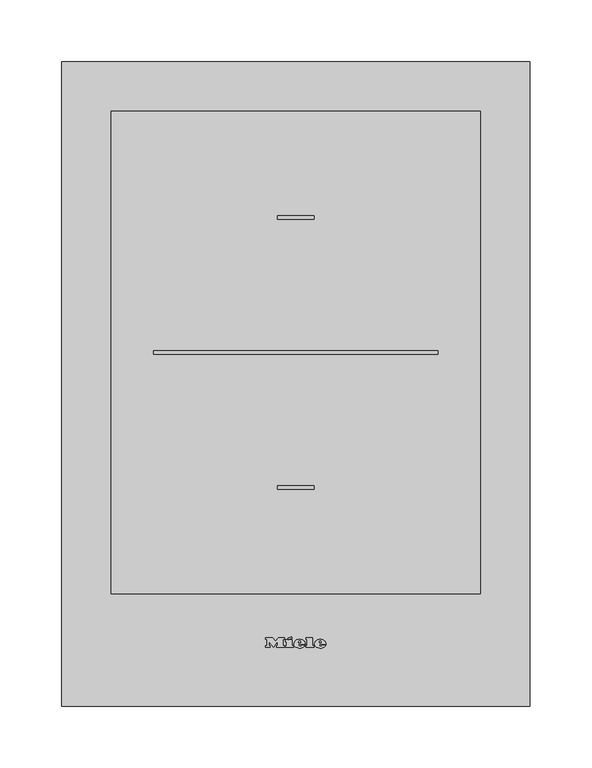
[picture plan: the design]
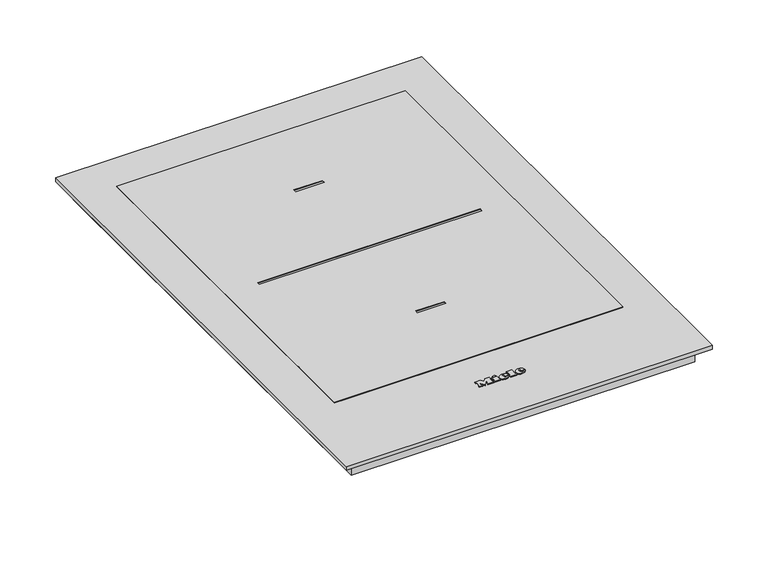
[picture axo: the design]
"""IFC4 building model written with IfcOpenShell, lengths in millimetres: proxy geometry."""

from ifc_helpers import new_model, si_unit, point, frame, frame_2d, origin, origin_with_axes, place, context, project, spatial, polyline, circle_curve, ellipse_curve, trimmed, segment, composite_curve, outline, extrude, source, transform, mapped, element, save
from ifc_brep_helpers import plane_surface, cylinder_surface, revolved_surface, extruded_surface, advanced_brep


def specialty_equipment_049aa171(model_context):
    return source(origin(), model_context, "Body", "SolidModel", [
        advanced_brep(
        [(19.06, 49.1959995, 4.9919765), (19.06, 50.0039992, 4.9925904), (24.412, 50.0039992, 4.9925904), (15.1, 50.0039992, 4.9925904), (17.3, 47.3, 4.990536), (24.276, 49.1959995, 4.9919765), (21.86, 49.1959995, 4.9919765), (19.956, 48.2999997, 4.9912958), (19.06, 51.0279989, 4.9933684), (19.06, 51.8999987, 4.9940309), (20.428, 51.8999987, 4.9940309), (20.428, 51.0279989, 4.9933684), (19.06, 49.1967592, 3.9919768), (19.956, 48.3007595, 3.9912961), (21.86, 49.1967592, 3.9919768), (24.276, 49.1967592, 3.9919768), (17.3, 47.3007598, 3.9905363), (15.1, 50.004759, 3.9925907), (24.412, 50.004759, 3.9925907), (19.06, 50.004759, 3.9925907), (19.06, 51.0287587, 3.9933687), (20.428, 51.0287587, 3.9933687), (20.428, 51.9007584, 3.9940312), (19.06, 51.9007584, 3.9940312)],
        [
            (0, 1),
            (1, 2),
            (2, 3, ellipse_curve(frame((19.756, 50.0039992, 4.9925904), z_axis=(0.0, -0.0007597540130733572, 0.9999997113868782), x_axis=(-1.0, 0.0, 0.0)), 4.656, 3.848)),
            (3, 4, circle_curve(frame((18.1960436, 50.2759991, 4.9927971), z_axis=(0.0, -0.0007597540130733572, 0.9999997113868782), x_axis=(0.0, -0.9999997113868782, -0.0007597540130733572)), 3.1079688)),
            (4, 5, circle_curve(frame((19.6627936, 52.3879985, 4.9944017), z_axis=(0.0, -0.0007597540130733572, 0.9999997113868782), x_axis=(0.0, -0.9999997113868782, -0.0007597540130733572)), 5.6098607)),
            (5, 6),
            (6, 7, circle_curve(frame((20.3470588, 49.9399992, 4.9925418), z_axis=(0.0, 0.0007597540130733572, -0.9999997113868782), x_axis=(0.0, -0.9999997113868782, -0.0007597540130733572)), 1.6859795)),
            (7, 0, circle_curve(frame((19.956, 49.1959995, 4.9919765), z_axis=(0.0, 0.0007597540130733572, -0.9999997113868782), x_axis=(0.0, -0.9999997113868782, -0.0007597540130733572)), 0.896)),
            (8, 9),
            (9, 10, circle_curve(frame((19.744, 51.8999987, 4.9940309), z_axis=(0.0, 0.0007597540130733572, -0.9999997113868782), x_axis=(0.0, -0.9999997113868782, -0.0007597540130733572)), 0.684)),
            (10, 11),
            (11, 8),
            (12, 13, circle_curve(frame((19.956, 49.1967592, 3.9919768), z_axis=(0.0, -0.0007597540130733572, 0.9999997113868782), x_axis=(0.0, -0.9999997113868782, -0.0007597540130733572)), 0.896)),
            (13, 14, circle_curve(frame((20.3470588, 49.940759, 3.9925421), z_axis=(0.0, -0.0007597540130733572, 0.9999997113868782), x_axis=(0.0, -0.9999997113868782, -0.0007597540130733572)), 1.6859795)),
            (14, 15),
            (15, 16, circle_curve(frame((19.6627936, 52.3887583, 3.994402), z_axis=(0.0, 0.0007597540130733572, -0.9999997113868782), x_axis=(0.0, -0.9999997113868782, -0.0007597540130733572)), 5.6098607)),
            (16, 17, circle_curve(frame((18.1960436, 50.2767589, 3.9927974), z_axis=(0.0, 0.0007597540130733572, -0.9999997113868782), x_axis=(0.0, -0.9999997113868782, -0.0007597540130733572)), 3.1079688)),
            (17, 18, ellipse_curve(frame((19.756, 50.004759, 3.9925907), z_axis=(0.0, 0.0007597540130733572, -0.9999997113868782), x_axis=(-1.0, 0.0, 0.0)), 4.656, 3.848)),
            (18, 19),
            (19, 12),
            (20, 21),
            (21, 22),
            (22, 23, circle_curve(frame((19.744, 51.9007584, 3.9940312), z_axis=(0.0, -0.0007597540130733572, 0.9999997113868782), x_axis=(0.0, -0.9999997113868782, -0.0007597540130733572)), 0.684)),
            (23, 20),
            (0, 12),
            (19, 1),
            (18, 2),
            (5, 15),
            (14, 6),
            (17, 3),
            (13, 7),
            (16, 4),
            (8, 20),
            (23, 9),
            (22, 10),
            (21, 11),
        ],
        [
            plane_surface(frame((19.06, 50.0039992, 4.9925904), z_axis=(0.0, -0.0007597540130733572, 0.9999997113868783), x_axis=(0.0, 0.9999997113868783, 0.0007597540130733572))),
            plane_surface(frame((19.06, 50.004759, 3.9925907), z_axis=(0.0, 0.0007597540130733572, -0.9999997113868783), x_axis=(0.0, -0.9999997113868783, -0.0007597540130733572))),
            plane_surface(frame((19.06, 49.1959995, 4.9919765), z_axis=(1.0, 0.0, 0.0), x_axis=(0.0, 0.0007597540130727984, -0.9999997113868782))),
            plane_surface(frame((19.06, 50.0039992, 4.9925904), z_axis=(0.0, -0.9999997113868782, -0.0007597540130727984), x_axis=(0.0, 0.0007597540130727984, -0.9999997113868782))),
            plane_surface(frame((24.276, 49.1959995, 4.9919765), z_axis=(0.0, 0.9999997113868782, 0.0007597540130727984), x_axis=(0.0, 0.0007597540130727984, -0.9999997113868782))),
            extruded_surface(trimmed(ellipse_curve(frame((19.756, 50.0055187, 2.992591), z_axis=(0.0, -0.0007597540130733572, 0.9999997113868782), x_axis=(-1.0, 0.0, 0.0)), 4.656, 3.848), [point((24.412, 50.0055187, 2.992591))], [point((15.1, 50.0055187, 2.992591))], True, "CARTESIAN"), (0.0, -0.0007597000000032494, 0.9999997), 0.9999999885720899),
            revolved_surface(polyline([(20.3470588, 48.25477998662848, 3.9912611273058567), (20.3470588, 48.25402023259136, 4.991260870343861)]), (20.3470588, 49.940759, 3.9925421), (0.0, 0.0007597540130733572, -0.9999997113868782)),
            revolved_surface(polyline([(19.956, 48.30075945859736, 3.9912960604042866), (19.956, 48.29999970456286, 4.991295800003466)]), (19.956, 49.1967592, 3.9919768), (0.0, 0.0007597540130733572, -0.9999997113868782)),
            cylinder_surface(frame((18.1960436, 50.2767589, 3.9927974), z_axis=(0.0, -0.0007597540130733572, 0.9999997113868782), x_axis=(0.0, -0.9999997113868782, -0.0007597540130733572)), 3.1079688),
            cylinder_surface(frame((19.6627936, 52.3887583, 3.994402), z_axis=(0.0, -0.0007597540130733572, 0.9999997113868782), x_axis=(0.0, -0.9999997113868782, -0.0007597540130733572)), 5.6098607),
            plane_surface(frame((19.06, 51.0279989, 4.9933684), z_axis=(1.0, 0.0, 0.0), x_axis=(0.0, 0.0007597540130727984, -0.9999997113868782))),
            revolved_surface(polyline([(19.744, 51.21675859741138, 3.9935115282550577), (19.744, 51.215998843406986, 4.993511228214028)]), (19.744, 51.9007584, 3.9940312), (0.0, 0.0007597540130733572, -0.9999997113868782)),
            plane_surface(frame((20.428, 51.8999987, 4.9940309), z_axis=(-1.0, 0.0, 0.0), x_axis=(0.0, 0.0007597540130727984, -0.9999997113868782))),
            plane_surface(frame((20.428, 51.0279989, 4.9933684), z_axis=(0.0, 0.9999997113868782, 0.0007597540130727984), x_axis=(0.0, 0.0007597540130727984, -0.9999997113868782))),
        ],
        [
            (0, [[1, 2, 3, 4, 5, 6, 7, 8], [9, 10, 11, 12]]),
            (1, [[13, 14, 15, 16, 17, 18, 19, 20], [21, 22, 23, 24]]),
            (2, [[-1, 25, -20, 26]]),
            (3, [[-2, -26, -19, 27]]),
            (4, [[-6, 28, -15, 29]]),
            (5, [[-3, -27, -18, 30]]),
            (6, [[-7, -29, -14, 31]]),
            (7, [[-8, -31, -13, -25]]),
            (8, [[-4, -30, -17, 32]]),
            (9, [[-5, -32, -16, -28]]),
            (10, [[-9, 33, -24, 34]]),
            (11, [[-10, -34, -23, 35]]),
            (12, [[-11, -35, -22, 36]]),
            (13, [[-12, -36, -21, -33]]),
        ],
    ),
        advanced_brep(
        [(2.364, 49.1959995, 4.9919765), (2.364, 50.0039992, 4.9925904), (7.716, 50.0039992, 4.9925904), (-1.596, 50.0039992, 4.9925904), (0.604, 47.3, 4.990536), (7.58, 49.1959995, 4.9919765), (5.164, 49.1959995, 4.9919765), (3.26, 48.2999997, 4.9912958), (2.364, 51.0279989, 4.9933684), (2.364, 51.8999987, 4.9940309), (3.732, 51.8999987, 4.9940309), (3.732, 51.0279989, 4.9933684), (2.364, 49.1967592, 3.9919768), (3.26, 48.3007595, 3.9912961), (5.164, 49.1967592, 3.9919768), (7.58, 49.1967592, 3.9919768), (0.604, 47.3007598, 3.9905363), (-1.596, 50.004759, 3.9925907), (7.716, 50.004759, 3.9925907), (2.364, 50.004759, 3.9925907), (2.364, 51.0287587, 3.9933687), (3.732, 51.0287587, 3.9933687), (3.732, 51.9007584, 3.9940312), (2.364, 51.9007584, 3.9940312)],
        [
            (0, 1),
            (1, 2),
            (2, 3, ellipse_curve(frame((3.06, 50.0039992, 4.9925904), z_axis=(0.0, -0.0007597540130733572, 0.9999997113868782), x_axis=(-1.0, 0.0, 0.0)), 4.656, 3.848)),
            (3, 4, circle_curve(frame((1.5000436, 50.2759991, 4.9927971), z_axis=(0.0, -0.0007597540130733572, 0.9999997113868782), x_axis=(0.0, -0.9999997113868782, -0.0007597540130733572)), 3.1079688)),
            (4, 5, circle_curve(frame((2.9667936, 52.3879985, 4.9944017), z_axis=(0.0, -0.0007597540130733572, 0.9999997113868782), x_axis=(0.0, -0.9999997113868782, -0.0007597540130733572)), 5.6098607)),
            (5, 6),
            (6, 7, circle_curve(frame((3.6510588, 49.9399992, 4.9925418), z_axis=(0.0, 0.0007597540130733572, -0.9999997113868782), x_axis=(0.0, -0.9999997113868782, -0.0007597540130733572)), 1.6859795)),
            (7, 0, circle_curve(frame((3.26, 49.1959995, 4.9919765), z_axis=(0.0, 0.0007597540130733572, -0.9999997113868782), x_axis=(0.0, -0.9999997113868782, -0.0007597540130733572)), 0.896)),
            (8, 9),
            (9, 10, circle_curve(frame((3.048, 51.8999987, 4.9940309), z_axis=(0.0, 0.0007597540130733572, -0.9999997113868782), x_axis=(0.0, -0.9999997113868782, -0.0007597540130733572)), 0.684)),
            (10, 11),
            (11, 8),
            (12, 13, circle_curve(frame((3.26, 49.1967592, 3.9919768), z_axis=(0.0, -0.0007597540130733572, 0.9999997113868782), x_axis=(0.0, -0.9999997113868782, -0.0007597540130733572)), 0.896)),
            (13, 14, circle_curve(frame((3.6510588, 49.940759, 3.9925421), z_axis=(0.0, -0.0007597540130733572, 0.9999997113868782), x_axis=(0.0, -0.9999997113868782, -0.0007597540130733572)), 1.6859795)),
            (14, 15),
            (15, 16, circle_curve(frame((2.9667936, 52.3887583, 3.994402), z_axis=(0.0, 0.0007597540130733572, -0.9999997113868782), x_axis=(0.0, -0.9999997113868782, -0.0007597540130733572)), 5.6098607)),
            (16, 17, circle_curve(frame((1.5000436, 50.2767589, 3.9927974), z_axis=(0.0, 0.0007597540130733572, -0.9999997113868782), x_axis=(0.0, -0.9999997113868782, -0.0007597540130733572)), 3.1079688)),
            (17, 18, ellipse_curve(frame((3.06, 50.004759, 3.9925907), z_axis=(0.0, 0.0007597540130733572, -0.9999997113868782), x_axis=(-1.0, 0.0, 0.0)), 4.656, 3.848)),
            (18, 19),
            (19, 12),
            (20, 21),
            (21, 22),
            (22, 23, circle_curve(frame((3.048, 51.9007584, 3.9940312), z_axis=(0.0, -0.0007597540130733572, 0.9999997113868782), x_axis=(0.0, -0.9999997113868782, -0.0007597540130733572)), 0.684)),
            (23, 20),
            (0, 12),
            (19, 1),
            (18, 2),
            (5, 15),
            (14, 6),
            (17, 3),
            (13, 7),
            (16, 4),
            (8, 20),
            (23, 9),
            (22, 10),
            (21, 11),
        ],
        [
            plane_surface(frame((2.364, 50.0039992, 4.9925904), z_axis=(0.0, -0.0007597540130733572, 0.9999997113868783), x_axis=(0.0, 0.9999997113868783, 0.0007597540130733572))),
            plane_surface(frame((2.364, 50.004759, 3.9925907), z_axis=(0.0, 0.0007597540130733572, -0.9999997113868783), x_axis=(0.0, -0.9999997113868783, -0.0007597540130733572))),
            plane_surface(frame((2.364, 49.1959995, 4.9919765), z_axis=(1.0, 0.0, 0.0), x_axis=(0.0, 0.0007597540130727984, -0.9999997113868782))),
            plane_surface(frame((2.364, 50.0039992, 4.9925904), z_axis=(0.0, -0.9999997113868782, -0.0007597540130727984), x_axis=(0.0, 0.0007597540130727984, -0.9999997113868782))),
            plane_surface(frame((7.58, 49.1959995, 4.9919765), z_axis=(0.0, 0.9999997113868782, 0.0007597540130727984), x_axis=(0.0, 0.0007597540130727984, -0.9999997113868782))),
            extruded_surface(trimmed(ellipse_curve(frame((3.06, 50.0055187, 2.992591), z_axis=(0.0, -0.0007597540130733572, 0.9999997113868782), x_axis=(-1.0, 0.0, 0.0)), 4.656, 3.848), [point((7.716, 50.0055187, 2.992591))], [point((-1.596, 50.0055187, 2.992591))], True, "CARTESIAN"), (0.0, -0.0007597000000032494, 0.9999997), 0.9999999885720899),
            revolved_surface(polyline([(3.6510588, 48.25477998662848, 3.9912611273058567), (3.6510588, 48.25402023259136, 4.991260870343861)]), (3.6510588, 49.940759, 3.9925421), (0.0, 0.0007597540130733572, -0.9999997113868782)),
            revolved_surface(polyline([(3.26, 48.30075945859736, 3.9912960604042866), (3.26, 48.29999970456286, 4.991295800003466)]), (3.26, 49.1967592, 3.9919768), (0.0, 0.0007597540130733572, -0.9999997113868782)),
            cylinder_surface(frame((1.5000436, 50.2767589, 3.9927974), z_axis=(0.0, -0.0007597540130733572, 0.9999997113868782), x_axis=(0.0, -0.9999997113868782, -0.0007597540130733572)), 3.1079688),
            cylinder_surface(frame((2.9667936, 52.3887583, 3.994402), z_axis=(0.0, -0.0007597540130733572, 0.9999997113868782), x_axis=(0.0, -0.9999997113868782, -0.0007597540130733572)), 5.6098607),
            plane_surface(frame((2.364, 51.0279989, 4.9933684), z_axis=(1.0, 0.0, 0.0), x_axis=(0.0, 0.0007597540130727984, -0.9999997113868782))),
            revolved_surface(polyline([(3.048, 51.21675859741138, 3.9935115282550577), (3.048, 51.215998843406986, 4.993511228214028)]), (3.048, 51.9007584, 3.9940312), (0.0, 0.0007597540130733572, -0.9999997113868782)),
            plane_surface(frame((3.732, 51.8999987, 4.9940309), z_axis=(-1.0, 0.0, 0.0), x_axis=(0.0, 0.0007597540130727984, -0.9999997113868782))),
            plane_surface(frame((3.732, 51.0279989, 4.9933684), z_axis=(0.0, 0.9999997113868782, 0.0007597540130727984), x_axis=(0.0, 0.0007597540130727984, -0.9999997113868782))),
        ],
        [
            (0, [[1, 2, 3, 4, 5, 6, 7, 8], [9, 10, 11, 12]]),
            (1, [[13, 14, 15, 16, 17, 18, 19, 20], [21, 22, 23, 24]]),
            (2, [[-1, 25, -20, 26]]),
            (3, [[-2, -26, -19, 27]]),
            (4, [[-6, 28, -15, 29]]),
            (5, [[-3, -27, -18, 30]]),
            (6, [[-7, -29, -14, 31]]),
            (7, [[-8, -31, -13, -25]]),
            (8, [[-4, -30, -17, 32]]),
            (9, [[-5, -32, -16, -28]]),
            (10, [[-9, 33, -24, 34]]),
            (11, [[-10, -34, -23, 35]]),
            (12, [[-11, -35, -22, 36]]),
            (13, [[-12, -36, -21, -33]]),
        ],
    ),
        extrude(outline(polyline([(0.0, 0.0), (-0.0109086, -2.9993294), (-1.4390415, -2.9920868), (-1.4315306, 0.0), (0.0, 0.0)])), frame((-6.38, 54.8287576, 3.9962558), z_axis=(0.0, -0.0007597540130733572, 0.9999997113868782), x_axis=(-0.42472021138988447, 0.9053243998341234, 0.0006878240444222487)), (0.0, 0.0, 1.0), 1.0),
        extrude(outline(polyline([(-0.4933908, 2.4141097), (-2.7800844, -2.4601583), (-7.0459742, -0.4588767), (-7.4401145, -1.2990179), (-8.6568709, -0.728194), (-5.9760369, 4.9862153), (-4.7592806, 4.4153913), (-5.1636142, 3.5535222), (-2.1941494, 2.16044), (-1.7898157, 3.022309), (-0.4933908, 2.4141097)])), frame((-6.38, 54.8287576, 3.9962558), z_axis=(0.0, -0.0007597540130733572, 0.9999997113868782), x_axis=(-0.42472021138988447, 0.9053243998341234, 0.0006878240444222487)), (0.0, 0.0, 1.0), 1.0),
        extrude(outline(polyline([(0.0, 0.0), (0.0, -1.304), (-5.504, -1.304), (-5.504, 5.3519999), (-6.488, 5.3519999), (-6.488, 6.6959999), (0.0, 6.6959999), (0.0, 5.3519999), (-0.96, 5.3519999), (-0.96, 0.0), (0.0, 0.0)])), frame((8.164, 53.9967578, 3.9956236), z_axis=(0.0, -0.0007597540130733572, 0.9999997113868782), x_axis=(-1.0, 0.0, 0.0)), (0.0, 0.0, 1.0), 1.0),
        extrude(outline(polyline([(0.0, 0.0), (0.0, -1.304), (-5.576, -1.304), (-7.92, 1.696), (-10.256, -1.304), (-15.128, -1.304), (-15.128, 0.0), (-14.112, 0.0), (-14.112, 5.3519999), (-15.128, 5.3519999), (-15.128, 6.6959999), (-8.744, 6.6959999), (-8.744, 5.3519999), (-9.728, 5.3519999), (-9.728, 1.8807776), (-6.136, 6.6959999), (-2.56, 1.9488753), (-2.56, 5.3519999), (-3.52, 5.3519999), (-3.52, 6.6959999), (0.0, 6.6959999), (0.0, 5.3519999), (-0.968, 5.3519999), (-0.968, 0.0), (0.0, 0.0)])), frame((-24.3, 53.9967578, 3.9956236), z_axis=(0.0, -0.0007597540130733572, 0.9999997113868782), x_axis=(-1.0, 0.0, 0.0)), (0.0, 0.0, 1.0), 1.0),
        extrude(outline(polyline([(189.0, 520.0), (189.0, 0.0), (-189.0, 0.0), (-189.0, 520.0), (189.0, 520.0)])), origin_with_axes(), (0.0, 0.0, 1.0), 4.0),
        extrude(outline(polyline([(-119.0, 91.3), (-119.0, 468.3), (119.0, 468.3), (119.0, 433.7), (153.5, 433.7), (153.5, 183.5), (119.0, 183.5), (119.0, 91.3), (-119.0, 91.3)])), frame((0.0, 0.0, -46.5), z_axis=(0.0, 0.0, 1.0), x_axis=(1.0, 0.0, 0.0)), (0.0, 0.0, 1.0), 29.7),
        extrude(outline(polyline([(177.5, 508.5), (177.5, 11.5), (-177.5, 11.5), (-177.5, 508.5), (177.5, 508.5)])), frame((0.0, 0.0, -16.8), z_axis=(0.0, 0.0, 1.0), x_axis=(1.0, 0.0, 0.0)), (0.0, 0.0, 1.0), 16.8),
        extrude(outline(polyline([(447.3772603, -29.0), (440.0, -29.0), (440.0, -27.7442961), (446.1215564, -27.7442961), (446.1215564, -24.4480734), (440.470889, -24.4480734), (440.470889, -23.1923696), (446.1215564, -23.1923696), (446.1215564, -20.2100729), (440.156963, -20.2100729), (440.156963, -18.954369), (447.3772603, -18.954369), (447.3772603, -29.0)])), frame((-150.0, 0.0, 0.0), z_axis=(1.0, 0.0, 0.0), x_axis=(0.0, 1.0, 0.0)), (0.0, 0.0, 1.0), 1.0),
        extrude(outline(polyline([(438.1164442, -29.0), (431.8379248, -29.0), (431.8379248, -27.7442961), (436.8607403, -27.7442961), (436.8607403, -18.954369), (438.1164442, -18.954369), (438.1164442, -29.0)])), frame((-150.0, 0.0, 0.0), z_axis=(1.0, 0.0, 0.0), x_axis=(0.0, 1.0, 0.0)), (0.0, 0.0, 1.0), 1.0),
        extrude(outline(composite_curve([segment(trimmed(circle_curve(frame_2d((440.0, -24.0)), 8.0), [point((448.0, -24.0))], [point((432.0, -24.0))], False, "CARTESIAN"), True, "CONTINUOUS"), segment(trimmed(circle_curve(frame_2d((440.0, -24.0)), 8.0), [point((432.0, -24.0))], [point((448.0, -24.0))], False, "CARTESIAN"), True, "CONTINUOUS")], self_intersect=False)), frame((-149.0, 0.0, 0.0), z_axis=(1.0, 0.0, 0.0), x_axis=(0.0, 1.0, 0.0)), (0.0, 0.0, 1.0), 30.0),
        extrude(outline(polyline([(149.0, 480.0), (149.0, 90.8), (-149.0, 90.8), (-149.0, 480.0), (149.0, 480.0)]), holes=[polyline([(14.7, 395.95), (-14.7, 395.95), (-14.7, 392.85), (14.7, 392.85), (14.7, 395.95)]), polyline([(115.0, 286.95), (-115.0, 286.95), (-115.0, 283.85), (115.0, 283.85), (115.0, 286.95)]), polyline([(14.7, 177.95), (-14.7, 177.95), (-14.7, 174.85), (14.7, 174.85), (14.7, 177.95)])]), frame((0.0, 0.0, 4.0), z_axis=(0.0, 0.0, 1.0), x_axis=(1.0, 0.0, 0.0)), (0.0, 0.0, 1.0), 1.0),
    ])


if __name__ == "__main__":
    model = new_model("IFC4")
    model_context = context("Model", 3, world=origin())
    ifc_project = project(units=[si_unit("LENGTHUNIT", "METRE", prefix="MILLI")], contexts=[model_context])
    site = spatial("IfcSite", under=ifc_project)
    building = spatial("IfcBuilding", under=site)
    placement = place(None, origin())
    specialty_equipment_shape = specialty_equipment_049aa171(model_context)
    element("IfcBuildingElementProxy", 1, Name="Specialty Equipment", at=placement, inside=building, context=model_context, shape_type="MappedRepresentation", body=[
        mapped(specialty_equipment_shape, transform((0.0, 0.0, 0.0), x_axis=(1.0, 0.0, 0.0), y_axis=(0.0, 1.0, 0.0), z_axis=(0.0, 0.0, 1.0))),
    ])
    save(model, "model.ifc")
